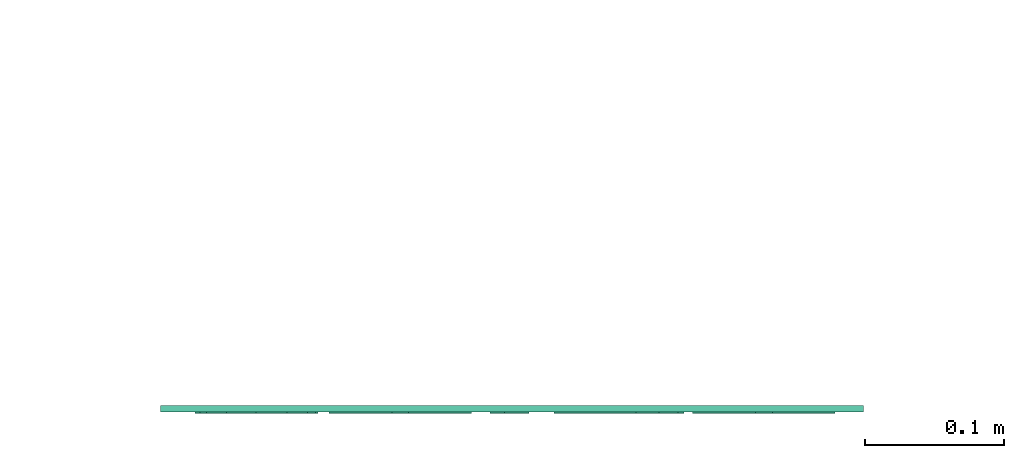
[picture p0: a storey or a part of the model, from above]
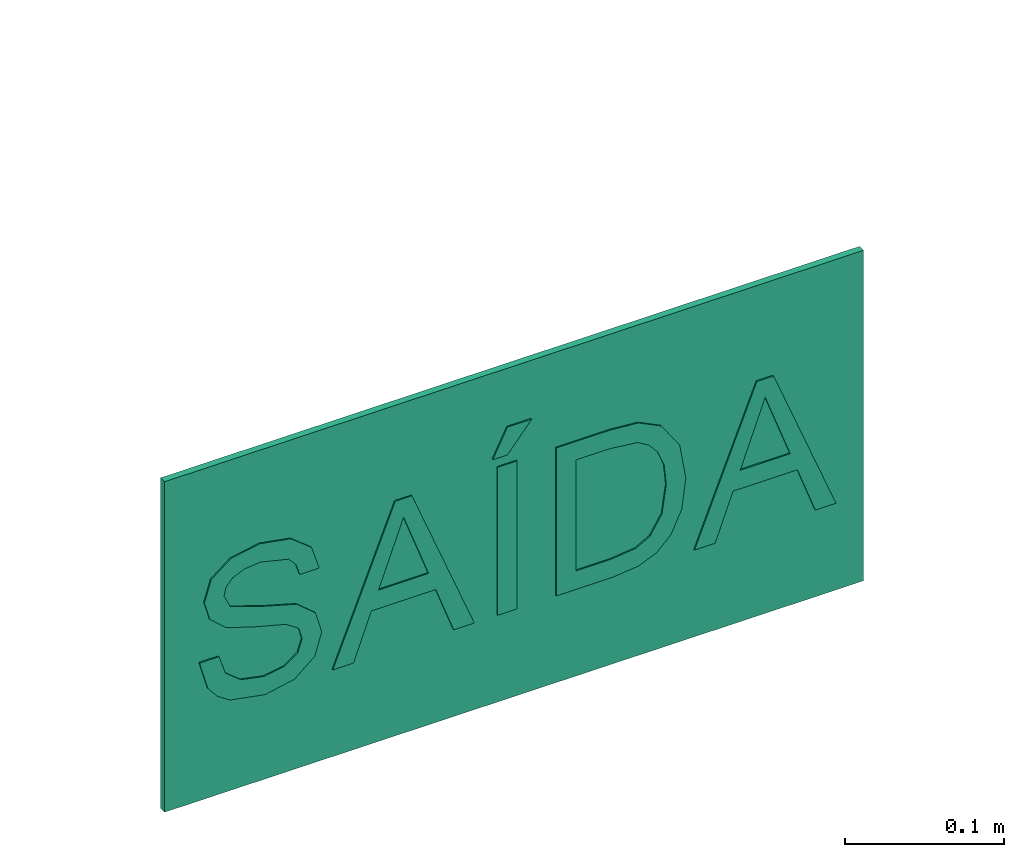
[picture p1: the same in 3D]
Properties of the parts of a building model (IFC2X3)

# File
Description: ViewDefinition [CoordinationView_V2.0]
File name: 0001
Time: 2021-06-16T13:05:48
Written by: The EXPRESS Data Manager Version 5.02.0100.07 : 28 Aug 2013
Made in: 21.1.11.27 - Exporter 21.1.11.27 - IU alternativa 21.1.11.27
Comment: STEP Physical File produced by: The EXPRESS Data Manager Version 5.02.0100.07 : 28 Aug 2013 * Module: EDMstepFileFactory/EDMstandAlone * Creation date: Wed Jun 16 13:05:48 2021 * Host: LAPTOP-D06TDN94 * Database: C:\Users\PAULAT~1\AppData\Local\Temp\4635c08b-ae0a-4f26-9cb2-6a9597644325\2c0f76c7-4ee5-430e-bad0-c115e6f64828\ifc * Database version: 5507 * Database creation date: Wed Jun 16 13:05:37 2021 * Schema: IFC2X3 * Model: DataRepository.ifc * Model creation date: Wed Jun 16 13:05:38 2021 * Header model: DataRepository.ifc_HeaderModel * Header model creation date: Wed Jun 16 13:05:38 2021 * EDMuser: sdai-user * EDMgroup: sdai-group * License ID and type: 5605 : Permanent license. Expiry date: * EDMstepFileFactory options: 020000

# IfcProject, 0001
LongName: Nome do projeto; Phase: Status do projeto

# IfcSite, Default
RefLatitude: -15, -52, 0, -120620; RefLongitude: -47, -55, 0, -114440; RefElevation: 0 m

# IfcBuilding, C.L. MONSENHOR ANTÔNIO SAMPAIO
LongName: C.L. MONSENHOR ANTÔNIO SAMPAIO
Pset_BuildingCommon - NumberOfStoreys: 2

# IfcBuildingStorey: Nível:8 mm Extremidade superior (2)
In: C.L. MONSENHOR ANTÔNIO SAMPAIO
Name | LongName | Elevation (m)
TÉRREO | TÉRREO | 0
Planta Baixa - Incêndio - Pav. Sup. | Planta Baixa - Incêndio - Pav. Sup. | 3.42

# IfcBuildingElementProxy: Acionador manual do sistema de detecção e alarme:Acionador manual do sistema de detecção e alarme (2)
In: TÉRREO
Type - Material: Plastico vermelho, Vidro, Vinil, flexível
Type - Pset_BuildingElementProxyCommon - Reference: Acionador manual do sistema de detecção e alarme
Type - Pset_QuantityTakeOff - Reference: Acionador manual do sistema de detecção e alarme
Pset_BuildingElementProxyCommon - sets with these values: 2
Name (Acionador manual do sistema de detecção e alarme:Acionador manual do sistema de detecção e alarme:...)
1890549
1890553

# IfcDistributionPort (2)
Description: Flow; FlowDirection: SOURCEANDSINK
Name
Port_1890553
Port_1890549

# IfcFlowTerminal: Central de Alarme de Incêndio:Central, Central de Alarme de Incêndio:Central:1888829
In: Planta Baixa - Incêndio - Pav. Sup.
Type - Material: <Unnamed>
Type - Pset_QuantityTakeOff - Reference: Central
Pset_DistributionFlowElementCommon - Reference: Central; sets with these values: 3

# IfcFlowTerminal: E2:10 metros (3)
Type - Material: VERMELHO
Type - Pset_QuantityTakeOff - Reference: 10 metros
Material: VERMELHO, Branco
Pset_DistributionFlowElementCommon - Reference: 10 metros; sets with these values: 3
Name (E2:10 metros:...) | In
1888838 | Planta Baixa - Incêndio - Pav. Sup.
1890563 | TÉRREO
1890566 | TÉRREO

# IfcFlowTerminal: E5:10 metros (5)
Type - Material: Branco
Type - Pset_QuantityTakeOff - Reference: 10 metros
Material: Branco, VERMELHO
Pset_DistributionFlowElementCommon - Reference: 10 metros; sets with these values: 3
Name (E5:10 metros:...) | In
1888857 | Planta Baixa - Incêndio - Pav. Sup.
1888860 | Planta Baixa - Incêndio - Pav. Sup.
1890536 | TÉRREO
1890539 | TÉRREO
1890542 | TÉRREO

# IfcFlowTerminal: E8:10 metros, E8:10 metros:1888820
In: Planta Baixa - Incêndio - Pav. Sup.
Type - Material: Branco
Type - Pset_QuantityTakeOff - Reference: 10 metros
Material: Branco, VERMELHO
Pset_DistributionFlowElementCommon - Reference: 10 metros; sets with these values: 3

# IfcFlowTerminal: Extintor Portatil:2-A20-BC (5)
Type - Material: Borracha, preta
Type - Pset_QuantityTakeOff - Reference: 2-A20-BC
Material: Borracha, preta, Cobre, Corpo extintor de incendio, Pintura de piso - Vermelho, Pintura de piso - Amarelo
Pset_DistributionFlowElementCommon - Reference: 2-A20-BC; sets with these values: 3
Name (Extintor Portatil:2-A20-BC:...) | In
1888847 | Planta Baixa - Incêndio - Pav. Sup.
1888850 | Planta Baixa - Incêndio - Pav. Sup.
1890511 | TÉRREO
1890514 | TÉRREO
1890517 | TÉRREO

# IfcFlowTerminal: Hidrante 60x90x17:Mangueira 30m - 2 lances, Hidrante 60x90x17:Mangueira 30m - 2 lances:1888806
In: Planta Baixa - Incêndio - Pav. Sup.
Type - Material: Cobre
Type - Pset_QuantityTakeOff - Reference: Mangueira 30m - 2 lances
Material: Cobre, Tecido mangueira de incêndio, Amarelo, Vidro, Aço pintado Vermelho
Pset_DistributionFlowElementCommon - Reference: Mangueira 30m - 2 lances; sets with these values: 3

# IfcFlowTerminal: Luminária de Emergência na parede vinculada:2W (34)
Type - Material: Origem de luz padrão
Type - Pset_DistributionFlowElementCommon - Reference: 2W
Type - Pset_QuantityTakeOff - Reference: 2W
Material: Vidro, Vinil, flexível
Pset_DistributionFlowElementCommon - sets with these values: 2
Name (Luminária de Emergência na parede vinculada:2W:...) | In
1868722 | TÉRREO
1885654 | TÉRREO
1888718 | Planta Baixa - Incêndio - Pav. Sup.
1888721 | Planta Baixa - Incêndio - Pav. Sup.
1888724 | Planta Baixa - Incêndio - Pav. Sup.
1888727 | Planta Baixa - Incêndio - Pav. Sup.
1888730 | Planta Baixa - Incêndio - Pav. Sup.
1888733 | Planta Baixa - Incêndio - Pav. Sup.
1888736 | Planta Baixa - Incêndio - Pav. Sup.
1888739 | Planta Baixa - Incêndio - Pav. Sup.
1888742 | Planta Baixa - Incêndio - Pav. Sup.
1888745 | Planta Baixa - Incêndio - Pav. Sup.
1888748 | Planta Baixa - Incêndio - Pav. Sup.
1888751 | Planta Baixa - Incêndio - Pav. Sup.
1888754 | Planta Baixa - Incêndio - Pav. Sup.
1888757 | Planta Baixa - Incêndio - Pav. Sup.
1890395 | TÉRREO
1890456 | TÉRREO
1890459 | TÉRREO
1890462 | TÉRREO
1890465 | TÉRREO
1890468 | TÉRREO
1890471 | TÉRREO
1890474 | TÉRREO
1890477 | TÉRREO
1890480 | TÉRREO
1890483 | TÉRREO
1890486 | TÉRREO
1890489 | TÉRREO
1890492 | TÉRREO
1890495 | TÉRREO
1890498 | TÉRREO
1890501 | TÉRREO
1890504 | TÉRREO

# IfcFlowTerminal: S12:10 metros, S12:10 metros:1890575
In: TÉRREO
Type - Material: Branco
Type - Pset_QuantityTakeOff - Reference: 10 metros
Material: Branco, VERDE
Pset_DistributionFlowElementCommon - Reference: 10 metros; sets with these values: 3

# IfcFlowTerminal: S12:20 metros, S12:20 metros:1885791
In: TÉRREO
Type - Material: Branco
Type - Pset_QuantityTakeOff - Reference: 20 metros
Material: Branco, VERDE
Pset_DistributionFlowElementCommon - Reference: 20 metros; sets with these values: 2

# IfcFlowTerminal: S14:10 metros, S14:10 metros:1890584
In: TÉRREO
Type - Material: Branco
Type - Pset_QuantityTakeOff - Reference: 10 metros
Material: Branco, VERDE
Pset_DistributionFlowElementCommon - Reference: 10 metros; sets with these values: 3

# IfcFlowTerminal: S1:10 metros (4)
Type - Material: Branco
Type - Pset_QuantityTakeOff - Reference: 10 metros
Material: Branco, VERDE
Pset_DistributionFlowElementCommon - Reference: 10 metros; sets with these values: 3
Name (S1:10 metros:...) | In
1888872 | Planta Baixa - Incêndio - Pav. Sup.
1890606 | TÉRREO
1890609 | TÉRREO
1890612 | TÉRREO

# IfcFlowTerminal: S2:10 metros (5)
Type - Material: Branco
Type - Pset_QuantityTakeOff - Reference: 10 metros
Material: Branco, VERDE
Pset_DistributionFlowElementCommon - Reference: 10 metros; sets with these values: 3
Name (S2:10 metros:...) | In
1888884 | Planta Baixa - Incêndio - Pav. Sup.
1888896 | Planta Baixa - Incêndio - Pav. Sup.
1890594 | TÉRREO
1890597 | TÉRREO
1890600 | TÉRREO

# IfcSlab: Piso:Genérico 300 mm, Piso:Genérico 300 mm:1887517
In: Planta Baixa - Incêndio - Pav. Sup.
Type - PredefinedType: FLOOR; Material: Material pré-definido de piso 0.3 m
Type - Pset_QuantityTakeOff - Reference: Genérico 300 mm
Type - Pset_ReinforcementBarPitchOfSlab - Reference: Genérico 300 mm
Type - Pset_SlabCommon - Reference: Genérico 300 mm; IsExternal: no
Pset_QuantityTakeOff - sets with these values: 2
Pset_SlabCommon - LoadBearing: no; PitchAngle: 0 deg
